VERSION 5.7 ;
  NOWIREEXTENSIONATPIN ON ;
  DIVIDERCHAR "/" ;
  BUSBITCHARS "[]" ;
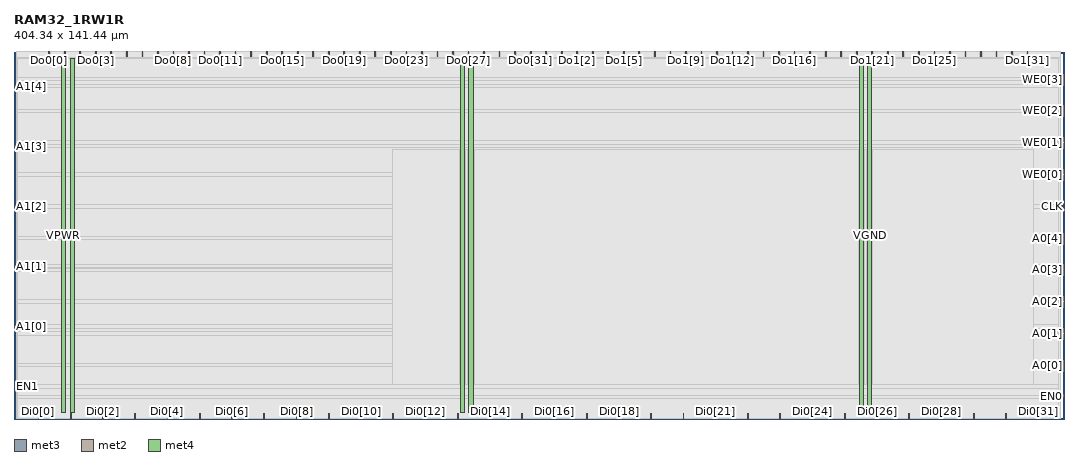
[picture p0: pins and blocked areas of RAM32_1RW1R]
MACRO RAM32_1RW1R
  CLASS BLOCK ;
  FOREIGN RAM32_1RW1R ;
  ORIGIN 0.000 0.000 ;
  SIZE 404.340 BY 141.440 ;
  PIN A0[0]
    DIRECTION INPUT ;
    USE SIGNAL ;
    ANTENNAGATEAREA 0.213000 ;
    PORT
      LAYER met3 ;
        RECT 402.340 20.440 404.340 21.040 ;
    END
  END A0[0]
  PIN A0[1]
    DIRECTION INPUT ;
    USE SIGNAL ;
    ANTENNAGATEAREA 0.213000 ;
    PORT
      LAYER met3 ;
        RECT 402.340 32.680 404.340 33.280 ;
    END
  END A0[1]
  PIN A0[2]
    DIRECTION INPUT ;
    USE SIGNAL ;
    ANTENNAGATEAREA 0.213000 ;
    PORT
      LAYER met3 ;
        RECT 402.340 44.920 404.340 45.520 ;
    END
  END A0[2]
  PIN A0[3]
    DIRECTION INPUT ;
    USE SIGNAL ;
    ANTENNAGATEAREA 0.213000 ;
    PORT
      LAYER met3 ;
        RECT 402.340 57.160 404.340 57.760 ;
    END
  END A0[3]
  PIN A0[4]
    DIRECTION INPUT ;
    USE SIGNAL ;
    ANTENNAGATEAREA 0.213000 ;
    PORT
      LAYER met3 ;
        RECT 402.340 69.400 404.340 70.000 ;
    END
  END A0[4]
  PIN A1[0]
    DIRECTION INPUT ;
    USE SIGNAL ;
    ANTENNAGATEAREA 0.213000 ;
    PORT
      LAYER met3 ;
        RECT 0.000 35.400 2.000 36.000 ;
    END
  END A1[0]
  PIN A1[1]
    DIRECTION INPUT ;
    USE SIGNAL ;
    ANTENNAGATEAREA 0.213000 ;
    PORT
      LAYER met3 ;
        RECT 0.000 58.520 2.000 59.120 ;
    END
  END A1[1]
  PIN A1[2]
    DIRECTION INPUT ;
    USE SIGNAL ;
    ANTENNAGATEAREA 0.213000 ;
    PORT
      LAYER met3 ;
        RECT 0.000 81.640 2.000 82.240 ;
    END
  END A1[2]
  PIN A1[3]
    DIRECTION INPUT ;
    USE SIGNAL ;
    ANTENNAGATEAREA 0.213000 ;
    PORT
      LAYER met3 ;
        RECT 0.000 104.760 2.000 105.360 ;
    END
  END A1[3]
  PIN A1[4]
    DIRECTION INPUT ;
    USE SIGNAL ;
    ANTENNAGATEAREA 0.213000 ;
    PORT
      LAYER met3 ;
        RECT 0.000 127.880 2.000 128.480 ;
    END
  END A1[4]
  PIN CLK
    DIRECTION INPUT ;
    USE SIGNAL ;
    ANTENNAGATEAREA 1.295400 ;
    ANTENNADIFFAREA 0.869400 ;
    PORT
      LAYER met3 ;
        RECT 402.340 81.640 404.340 82.240 ;
    END
  END CLK
  PIN Di0[0]
    DIRECTION INPUT ;
    USE SIGNAL ;
    ANTENNAGATEAREA 0.852000 ;
    PORT
      LAYER met2 ;
        RECT 9.290 0.000 9.570 2.000 ;
    END
  END Di0[0]
  PIN Di0[10]
    DIRECTION INPUT ;
    USE SIGNAL ;
    ANTENNAGATEAREA 0.852000 ;
    PORT
      LAYER met2 ;
        RECT 133.490 0.000 133.770 2.000 ;
    END
  END Di0[10]
  PIN Di0[11]
    DIRECTION INPUT ;
    USE SIGNAL ;
    ANTENNAGATEAREA 0.852000 ;
    PORT
      LAYER met2 ;
        RECT 145.910 0.000 146.190 2.000 ;
    END
  END Di0[11]
  PIN Di0[12]
    DIRECTION INPUT ;
    USE SIGNAL ;
    ANTENNAGATEAREA 0.852000 ;
    PORT
      LAYER met2 ;
        RECT 158.330 0.000 158.610 2.000 ;
    END
  END Di0[12]
  PIN Di0[13]
    DIRECTION INPUT ;
    USE SIGNAL ;
    ANTENNAGATEAREA 0.852000 ;
    PORT
      LAYER met2 ;
        RECT 170.750 0.000 171.030 2.000 ;
    END
  END Di0[13]
  PIN Di0[14]
    DIRECTION INPUT ;
    USE SIGNAL ;
    ANTENNAGATEAREA 0.852000 ;
    PORT
      LAYER met2 ;
        RECT 183.170 0.000 183.450 2.000 ;
    END
  END Di0[14]
  PIN Di0[15]
    DIRECTION INPUT ;
    USE SIGNAL ;
    ANTENNAGATEAREA 0.852000 ;
    PORT
      LAYER met2 ;
        RECT 195.590 0.000 195.870 2.000 ;
    END
  END Di0[15]
  PIN Di0[16]
    DIRECTION INPUT ;
    USE SIGNAL ;
    ANTENNAGATEAREA 0.852000 ;
    PORT
      LAYER met2 ;
        RECT 208.010 0.000 208.290 2.000 ;
    END
  END Di0[16]
  PIN Di0[17]
    DIRECTION INPUT ;
    USE SIGNAL ;
    ANTENNAGATEAREA 0.852000 ;
    PORT
      LAYER met2 ;
        RECT 220.430 0.000 220.710 2.000 ;
    END
  END Di0[17]
  PIN Di0[18]
    DIRECTION INPUT ;
    USE SIGNAL ;
    ANTENNAGATEAREA 0.852000 ;
    PORT
      LAYER met2 ;
        RECT 232.850 0.000 233.130 2.000 ;
    END
  END Di0[18]
  PIN Di0[19]
    DIRECTION INPUT ;
    USE SIGNAL ;
    ANTENNAGATEAREA 0.852000 ;
    PORT
      LAYER met2 ;
        RECT 245.270 0.000 245.550 2.000 ;
    END
  END Di0[19]
  PIN Di0[1]
    DIRECTION INPUT ;
    USE SIGNAL ;
    ANTENNAGATEAREA 0.852000 ;
    PORT
      LAYER met2 ;
        RECT 21.710 0.000 21.990 2.000 ;
    END
  END Di0[1]
  PIN Di0[20]
    DIRECTION INPUT ;
    USE SIGNAL ;
    ANTENNAGATEAREA 0.852000 ;
    PORT
      LAYER met2 ;
        RECT 257.690 0.000 257.970 2.000 ;
    END
  END Di0[20]
  PIN Di0[21]
    DIRECTION INPUT ;
    USE SIGNAL ;
    ANTENNAGATEAREA 0.852000 ;
    PORT
      LAYER met2 ;
        RECT 270.110 0.000 270.390 2.000 ;
    END
  END Di0[21]
  PIN Di0[22]
    DIRECTION INPUT ;
    USE SIGNAL ;
    ANTENNAGATEAREA 0.852000 ;
    PORT
      LAYER met2 ;
        RECT 282.530 0.000 282.810 2.000 ;
    END
  END Di0[22]
  PIN Di0[23]
    DIRECTION INPUT ;
    USE SIGNAL ;
    ANTENNAGATEAREA 0.852000 ;
    PORT
      LAYER met2 ;
        RECT 294.950 0.000 295.230 2.000 ;
    END
  END Di0[23]
  PIN Di0[24]
    DIRECTION INPUT ;
    USE SIGNAL ;
    ANTENNAGATEAREA 0.852000 ;
    PORT
      LAYER met2 ;
        RECT 307.370 0.000 307.650 2.000 ;
    END
  END Di0[24]
  PIN Di0[25]
    DIRECTION INPUT ;
    USE SIGNAL ;
    ANTENNAGATEAREA 0.852000 ;
    PORT
      LAYER met2 ;
        RECT 319.790 0.000 320.070 2.000 ;
    END
  END Di0[25]
  PIN Di0[26]
    DIRECTION INPUT ;
    USE SIGNAL ;
    ANTENNAGATEAREA 0.852000 ;
    PORT
      LAYER met2 ;
        RECT 332.210 0.000 332.490 2.000 ;
    END
  END Di0[26]
  PIN Di0[27]
    DIRECTION INPUT ;
    USE SIGNAL ;
    ANTENNAGATEAREA 0.852000 ;
    PORT
      LAYER met2 ;
        RECT 344.630 0.000 344.910 2.000 ;
    END
  END Di0[27]
  PIN Di0[28]
    DIRECTION INPUT ;
    USE SIGNAL ;
    ANTENNAGATEAREA 0.852000 ;
    PORT
      LAYER met2 ;
        RECT 357.050 0.000 357.330 2.000 ;
    END
  END Di0[28]
  PIN Di0[29]
    DIRECTION INPUT ;
    USE SIGNAL ;
    ANTENNAGATEAREA 0.852000 ;
    PORT
      LAYER met2 ;
        RECT 369.470 0.000 369.750 2.000 ;
    END
  END Di0[29]
  PIN Di0[2]
    DIRECTION INPUT ;
    USE SIGNAL ;
    ANTENNAGATEAREA 0.852000 ;
    PORT
      LAYER met2 ;
        RECT 34.130 0.000 34.410 2.000 ;
    END
  END Di0[2]
  PIN Di0[30]
    DIRECTION INPUT ;
    USE SIGNAL ;
    ANTENNAGATEAREA 0.852000 ;
    PORT
      LAYER met2 ;
        RECT 381.890 0.000 382.170 2.000 ;
    END
  END Di0[30]
  PIN Di0[31]
    DIRECTION INPUT ;
    USE SIGNAL ;
    ANTENNAGATEAREA 0.852000 ;
    PORT
      LAYER met2 ;
        RECT 394.310 0.000 394.590 2.000 ;
    END
  END Di0[31]
  PIN Di0[3]
    DIRECTION INPUT ;
    USE SIGNAL ;
    ANTENNAGATEAREA 0.852000 ;
    PORT
      LAYER met2 ;
        RECT 46.550 0.000 46.830 2.000 ;
    END
  END Di0[3]
  PIN Di0[4]
    DIRECTION INPUT ;
    USE SIGNAL ;
    ANTENNAGATEAREA 0.852000 ;
    PORT
      LAYER met2 ;
        RECT 58.970 0.000 59.250 2.000 ;
    END
  END Di0[4]
  PIN Di0[5]
    DIRECTION INPUT ;
    USE SIGNAL ;
    ANTENNAGATEAREA 0.852000 ;
    PORT
      LAYER met2 ;
        RECT 71.390 0.000 71.670 2.000 ;
    END
  END Di0[5]
  PIN Di0[6]
    DIRECTION INPUT ;
    USE SIGNAL ;
    ANTENNAGATEAREA 0.852000 ;
    PORT
      LAYER met2 ;
        RECT 83.810 0.000 84.090 2.000 ;
    END
  END Di0[6]
  PIN Di0[7]
    DIRECTION INPUT ;
    USE SIGNAL ;
    ANTENNAGATEAREA 0.852000 ;
    PORT
      LAYER met2 ;
        RECT 96.230 0.000 96.510 2.000 ;
    END
  END Di0[7]
  PIN Di0[8]
    DIRECTION INPUT ;
    USE SIGNAL ;
    ANTENNAGATEAREA 0.852000 ;
    PORT
      LAYER met2 ;
        RECT 108.650 0.000 108.930 2.000 ;
    END
  END Di0[8]
  PIN Di0[9]
    DIRECTION INPUT ;
    USE SIGNAL ;
    ANTENNAGATEAREA 0.852000 ;
    PORT
      LAYER met2 ;
        RECT 121.070 0.000 121.350 2.000 ;
    END
  END Di0[9]
  PIN Do0[0]
    DIRECTION OUTPUT ;
    USE SIGNAL ;
    ANTENNADIFFAREA 0.429000 ;
    PORT
      LAYER met2 ;
        RECT 13.430 139.440 13.710 141.440 ;
    END
  END Do0[0]
  PIN Do0[10]
    DIRECTION OUTPUT ;
    USE SIGNAL ;
    ANTENNADIFFAREA 0.429000 ;
    PORT
      LAYER met2 ;
        RECT 73.230 139.440 73.510 141.440 ;
    END
  END Do0[10]
  PIN Do0[11]
    DIRECTION OUTPUT ;
    USE SIGNAL ;
    ANTENNADIFFAREA 0.429000 ;
    PORT
      LAYER met2 ;
        RECT 79.210 139.440 79.490 141.440 ;
    END
  END Do0[11]
  PIN Do0[12]
    DIRECTION OUTPUT ;
    USE SIGNAL ;
    ANTENNADIFFAREA 0.429000 ;
    PORT
      LAYER met2 ;
        RECT 85.190 139.440 85.470 141.440 ;
    END
  END Do0[12]
  PIN Do0[13]
    DIRECTION OUTPUT ;
    USE SIGNAL ;
    ANTENNADIFFAREA 0.429000 ;
    PORT
      LAYER met2 ;
        RECT 91.170 139.440 91.450 141.440 ;
    END
  END Do0[13]
  PIN Do0[14]
    DIRECTION OUTPUT ;
    USE SIGNAL ;
    ANTENNADIFFAREA 0.429000 ;
    PORT
      LAYER met2 ;
        RECT 97.150 139.440 97.430 141.440 ;
    END
  END Do0[14]
  PIN Do0[15]
    DIRECTION OUTPUT ;
    USE SIGNAL ;
    ANTENNADIFFAREA 0.429000 ;
    PORT
      LAYER met2 ;
        RECT 103.130 139.440 103.410 141.440 ;
    END
  END Do0[15]
  PIN Do0[16]
    DIRECTION OUTPUT ;
    USE SIGNAL ;
    ANTENNADIFFAREA 0.429000 ;
    PORT
      LAYER met2 ;
        RECT 109.110 139.440 109.390 141.440 ;
    END
  END Do0[16]
  PIN Do0[17]
    DIRECTION OUTPUT ;
    USE SIGNAL ;
    ANTENNADIFFAREA 0.429000 ;
    PORT
      LAYER met2 ;
        RECT 115.090 139.440 115.370 141.440 ;
    END
  END Do0[17]
  PIN Do0[18]
    DIRECTION OUTPUT ;
    USE SIGNAL ;
    ANTENNADIFFAREA 0.429000 ;
    PORT
      LAYER met2 ;
        RECT 121.070 139.440 121.350 141.440 ;
    END
  END Do0[18]
  PIN Do0[19]
    DIRECTION OUTPUT ;
    USE SIGNAL ;
    ANTENNADIFFAREA 0.429000 ;
    PORT
      LAYER met2 ;
        RECT 127.050 139.440 127.330 141.440 ;
    END
  END Do0[19]
  PIN Do0[1]
    DIRECTION OUTPUT ;
    USE SIGNAL ;
    ANTENNADIFFAREA 0.429000 ;
    PORT
      LAYER met2 ;
        RECT 19.410 139.440 19.690 141.440 ;
    END
  END Do0[1]
  PIN Do0[20]
    DIRECTION OUTPUT ;
    USE SIGNAL ;
    ANTENNADIFFAREA 0.429000 ;
    PORT
      LAYER met2 ;
        RECT 133.030 139.440 133.310 141.440 ;
    END
  END Do0[20]
  PIN Do0[21]
    DIRECTION OUTPUT ;
    USE SIGNAL ;
    ANTENNADIFFAREA 0.429000 ;
    PORT
      LAYER met2 ;
        RECT 139.010 139.440 139.290 141.440 ;
    END
  END Do0[21]
  PIN Do0[22]
    DIRECTION OUTPUT ;
    USE SIGNAL ;
    ANTENNADIFFAREA 0.429000 ;
    PORT
      LAYER met2 ;
        RECT 144.990 139.440 145.270 141.440 ;
    END
  END Do0[22]
  PIN Do0[23]
    DIRECTION OUTPUT ;
    USE SIGNAL ;
    ANTENNADIFFAREA 0.429000 ;
    PORT
      LAYER met2 ;
        RECT 150.970 139.440 151.250 141.440 ;
    END
  END Do0[23]
  PIN Do0[24]
    DIRECTION OUTPUT ;
    USE SIGNAL ;
    ANTENNADIFFAREA 0.429000 ;
    PORT
      LAYER met2 ;
        RECT 156.950 139.440 157.230 141.440 ;
    END
  END Do0[24]
  PIN Do0[25]
    DIRECTION OUTPUT ;
    USE SIGNAL ;
    ANTENNADIFFAREA 0.429000 ;
    PORT
      LAYER met2 ;
        RECT 162.930 139.440 163.210 141.440 ;
    END
  END Do0[25]
  PIN Do0[26]
    DIRECTION OUTPUT ;
    USE SIGNAL ;
    ANTENNADIFFAREA 0.429000 ;
    PORT
      LAYER met2 ;
        RECT 168.910 139.440 169.190 141.440 ;
    END
  END Do0[26]
  PIN Do0[27]
    DIRECTION OUTPUT ;
    USE SIGNAL ;
    ANTENNADIFFAREA 0.429000 ;
    PORT
      LAYER met2 ;
        RECT 174.890 139.440 175.170 141.440 ;
    END
  END Do0[27]
  PIN Do0[28]
    DIRECTION OUTPUT ;
    USE SIGNAL ;
    ANTENNADIFFAREA 0.429000 ;
    PORT
      LAYER met2 ;
        RECT 180.870 139.440 181.150 141.440 ;
    END
  END Do0[28]
  PIN Do0[29]
    DIRECTION OUTPUT ;
    USE SIGNAL ;
    ANTENNADIFFAREA 0.429000 ;
    PORT
      LAYER met2 ;
        RECT 186.850 139.440 187.130 141.440 ;
    END
  END Do0[29]
  PIN Do0[2]
    DIRECTION OUTPUT ;
    USE SIGNAL ;
    ANTENNADIFFAREA 0.429000 ;
    PORT
      LAYER met2 ;
        RECT 25.390 139.440 25.670 141.440 ;
    END
  END Do0[2]
  PIN Do0[30]
    DIRECTION OUTPUT ;
    USE SIGNAL ;
    ANTENNADIFFAREA 0.429000 ;
    PORT
      LAYER met2 ;
        RECT 192.830 139.440 193.110 141.440 ;
    END
  END Do0[30]
  PIN Do0[31]
    DIRECTION OUTPUT ;
    USE SIGNAL ;
    ANTENNADIFFAREA 0.429000 ;
    PORT
      LAYER met2 ;
        RECT 198.810 139.440 199.090 141.440 ;
    END
  END Do0[31]
  PIN Do0[3]
    DIRECTION OUTPUT ;
    USE SIGNAL ;
    ANTENNADIFFAREA 0.429000 ;
    PORT
      LAYER met2 ;
        RECT 31.370 139.440 31.650 141.440 ;
    END
  END Do0[3]
  PIN Do0[4]
    DIRECTION OUTPUT ;
    USE SIGNAL ;
    ANTENNADIFFAREA 0.429000 ;
    PORT
      LAYER met2 ;
        RECT 37.350 139.440 37.630 141.440 ;
    END
  END Do0[4]
  PIN Do0[5]
    DIRECTION OUTPUT ;
    USE SIGNAL ;
    ANTENNADIFFAREA 0.429000 ;
    PORT
      LAYER met2 ;
        RECT 43.330 139.440 43.610 141.440 ;
    END
  END Do0[5]
  PIN Do0[6]
    DIRECTION OUTPUT ;
    USE SIGNAL ;
    ANTENNADIFFAREA 0.429000 ;
    PORT
      LAYER met2 ;
        RECT 49.310 139.440 49.590 141.440 ;
    END
  END Do0[6]
  PIN Do0[7]
    DIRECTION OUTPUT ;
    USE SIGNAL ;
    ANTENNADIFFAREA 0.429000 ;
    PORT
      LAYER met2 ;
        RECT 55.290 139.440 55.570 141.440 ;
    END
  END Do0[7]
  PIN Do0[8]
    DIRECTION OUTPUT ;
    USE SIGNAL ;
    ANTENNADIFFAREA 0.429000 ;
    PORT
      LAYER met2 ;
        RECT 61.270 139.440 61.550 141.440 ;
    END
  END Do0[8]
  PIN Do0[9]
    DIRECTION OUTPUT ;
    USE SIGNAL ;
    ANTENNADIFFAREA 0.429000 ;
    PORT
      LAYER met2 ;
        RECT 67.250 139.440 67.530 141.440 ;
    END
  END Do0[9]
  PIN Do1[0]
    DIRECTION OUTPUT ;
    USE SIGNAL ;
    ANTENNADIFFAREA 0.429000 ;
    PORT
      LAYER met2 ;
        RECT 204.790 139.440 205.070 141.440 ;
    END
  END Do1[0]
  PIN Do1[10]
    DIRECTION OUTPUT ;
    USE SIGNAL ;
    ANTENNADIFFAREA 0.429000 ;
    PORT
      LAYER met2 ;
        RECT 264.590 139.440 264.870 141.440 ;
    END
  END Do1[10]
  PIN Do1[11]
    DIRECTION OUTPUT ;
    USE SIGNAL ;
    ANTENNADIFFAREA 0.429000 ;
    PORT
      LAYER met2 ;
        RECT 270.570 139.440 270.850 141.440 ;
    END
  END Do1[11]
  PIN Do1[12]
    DIRECTION OUTPUT ;
    USE SIGNAL ;
    ANTENNADIFFAREA 0.429000 ;
    PORT
      LAYER met2 ;
        RECT 276.550 139.440 276.830 141.440 ;
    END
  END Do1[12]
  PIN Do1[13]
    DIRECTION OUTPUT ;
    USE SIGNAL ;
    ANTENNADIFFAREA 0.429000 ;
    PORT
      LAYER met2 ;
        RECT 282.530 139.440 282.810 141.440 ;
    END
  END Do1[13]
  PIN Do1[14]
    DIRECTION OUTPUT ;
    USE SIGNAL ;
    ANTENNADIFFAREA 0.429000 ;
    PORT
      LAYER met2 ;
        RECT 288.510 139.440 288.790 141.440 ;
    END
  END Do1[14]
  PIN Do1[15]
    DIRECTION OUTPUT ;
    USE SIGNAL ;
    ANTENNADIFFAREA 0.429000 ;
    PORT
      LAYER met2 ;
        RECT 294.490 139.440 294.770 141.440 ;
    END
  END Do1[15]
  PIN Do1[16]
    DIRECTION OUTPUT ;
    USE SIGNAL ;
    ANTENNADIFFAREA 0.429000 ;
    PORT
      LAYER met2 ;
        RECT 300.470 139.440 300.750 141.440 ;
    END
  END Do1[16]
  PIN Do1[17]
    DIRECTION OUTPUT ;
    USE SIGNAL ;
    ANTENNADIFFAREA 0.429000 ;
    PORT
      LAYER met2 ;
        RECT 306.450 139.440 306.730 141.440 ;
    END
  END Do1[17]
  PIN Do1[18]
    DIRECTION OUTPUT ;
    USE SIGNAL ;
    ANTENNADIFFAREA 0.429000 ;
    PORT
      LAYER met2 ;
        RECT 312.430 139.440 312.710 141.440 ;
    END
  END Do1[18]
  PIN Do1[19]
    DIRECTION OUTPUT ;
    USE SIGNAL ;
    ANTENNADIFFAREA 0.429000 ;
    PORT
      LAYER met2 ;
        RECT 318.410 139.440 318.690 141.440 ;
    END
  END Do1[19]
  PIN Do1[1]
    DIRECTION OUTPUT ;
    USE SIGNAL ;
    ANTENNADIFFAREA 0.429000 ;
    PORT
      LAYER met2 ;
        RECT 210.770 139.440 211.050 141.440 ;
    END
  END Do1[1]
  PIN Do1[20]
    DIRECTION OUTPUT ;
    USE SIGNAL ;
    ANTENNADIFFAREA 0.429000 ;
    PORT
      LAYER met2 ;
        RECT 324.390 139.440 324.670 141.440 ;
    END
  END Do1[20]
  PIN Do1[21]
    DIRECTION OUTPUT ;
    USE SIGNAL ;
    ANTENNADIFFAREA 0.429000 ;
    PORT
      LAYER met2 ;
        RECT 330.370 139.440 330.650 141.440 ;
    END
  END Do1[21]
  PIN Do1[22]
    DIRECTION OUTPUT ;
    USE SIGNAL ;
    ANTENNADIFFAREA 0.429000 ;
    PORT
      LAYER met2 ;
        RECT 336.350 139.440 336.630 141.440 ;
    END
  END Do1[22]
  PIN Do1[23]
    DIRECTION OUTPUT ;
    USE SIGNAL ;
    ANTENNADIFFAREA 0.429000 ;
    PORT
      LAYER met2 ;
        RECT 342.330 139.440 342.610 141.440 ;
    END
  END Do1[23]
  PIN Do1[24]
    DIRECTION OUTPUT ;
    USE SIGNAL ;
    ANTENNADIFFAREA 0.429000 ;
    PORT
      LAYER met2 ;
        RECT 348.310 139.440 348.590 141.440 ;
    END
  END Do1[24]
  PIN Do1[25]
    DIRECTION OUTPUT ;
    USE SIGNAL ;
    ANTENNADIFFAREA 0.429000 ;
    PORT
      LAYER met2 ;
        RECT 354.290 139.440 354.570 141.440 ;
    END
  END Do1[25]
  PIN Do1[26]
    DIRECTION OUTPUT ;
    USE SIGNAL ;
    ANTENNADIFFAREA 0.429000 ;
    PORT
      LAYER met2 ;
        RECT 360.270 139.440 360.550 141.440 ;
    END
  END Do1[26]
  PIN Do1[27]
    DIRECTION OUTPUT ;
    USE SIGNAL ;
    ANTENNADIFFAREA 0.429000 ;
    PORT
      LAYER met2 ;
        RECT 366.250 139.440 366.530 141.440 ;
    END
  END Do1[27]
  PIN Do1[28]
    DIRECTION OUTPUT ;
    USE SIGNAL ;
    ANTENNADIFFAREA 0.429000 ;
    PORT
      LAYER met2 ;
        RECT 372.230 139.440 372.510 141.440 ;
    END
  END Do1[28]
  PIN Do1[29]
    DIRECTION OUTPUT ;
    USE SIGNAL ;
    ANTENNADIFFAREA 0.429000 ;
    PORT
      LAYER met2 ;
        RECT 378.210 139.440 378.490 141.440 ;
    END
  END Do1[29]
  PIN Do1[2]
    DIRECTION OUTPUT ;
    USE SIGNAL ;
    ANTENNADIFFAREA 0.429000 ;
    PORT
      LAYER met2 ;
        RECT 216.750 139.440 217.030 141.440 ;
    END
  END Do1[2]
  PIN Do1[30]
    DIRECTION OUTPUT ;
    USE SIGNAL ;
    ANTENNADIFFAREA 0.429000 ;
    PORT
      LAYER met2 ;
        RECT 384.190 139.440 384.470 141.440 ;
    END
  END Do1[30]
  PIN Do1[31]
    DIRECTION OUTPUT ;
    USE SIGNAL ;
    ANTENNADIFFAREA 0.429000 ;
    PORT
      LAYER met2 ;
        RECT 390.170 139.440 390.450 141.440 ;
    END
  END Do1[31]
  PIN Do1[3]
    DIRECTION OUTPUT ;
    USE SIGNAL ;
    ANTENNADIFFAREA 0.429000 ;
    PORT
      LAYER met2 ;
        RECT 222.730 139.440 223.010 141.440 ;
    END
  END Do1[3]
  PIN Do1[4]
    DIRECTION OUTPUT ;
    USE SIGNAL ;
    ANTENNADIFFAREA 0.429000 ;
    PORT
      LAYER met2 ;
        RECT 228.710 139.440 228.990 141.440 ;
    END
  END Do1[4]
  PIN Do1[5]
    DIRECTION OUTPUT ;
    USE SIGNAL ;
    ANTENNADIFFAREA 0.429000 ;
    PORT
      LAYER met2 ;
        RECT 234.690 139.440 234.970 141.440 ;
    END
  END Do1[5]
  PIN Do1[6]
    DIRECTION OUTPUT ;
    USE SIGNAL ;
    ANTENNADIFFAREA 0.429000 ;
    PORT
      LAYER met2 ;
        RECT 240.670 139.440 240.950 141.440 ;
    END
  END Do1[6]
  PIN Do1[7]
    DIRECTION OUTPUT ;
    USE SIGNAL ;
    ANTENNADIFFAREA 0.429000 ;
    PORT
      LAYER met2 ;
        RECT 246.650 139.440 246.930 141.440 ;
    END
  END Do1[7]
  PIN Do1[8]
    DIRECTION OUTPUT ;
    USE SIGNAL ;
    ANTENNADIFFAREA 0.429000 ;
    PORT
      LAYER met2 ;
        RECT 252.630 139.440 252.910 141.440 ;
    END
  END Do1[8]
  PIN Do1[9]
    DIRECTION OUTPUT ;
    USE SIGNAL ;
    ANTENNADIFFAREA 0.429000 ;
    PORT
      LAYER met2 ;
        RECT 258.610 139.440 258.890 141.440 ;
    END
  END Do1[9]
  PIN EN0
    DIRECTION INPUT ;
    USE SIGNAL ;
    ANTENNAGATEAREA 0.213000 ;
    PORT
      LAYER met3 ;
        RECT 402.340 8.200 404.340 8.800 ;
    END
  END EN0
  PIN EN1
    DIRECTION INPUT ;
    USE SIGNAL ;
    ANTENNAGATEAREA 0.213000 ;
    PORT
      LAYER met3 ;
        RECT 0.000 12.280 2.000 12.880 ;
    END
  END EN1
  PIN VGND
    DIRECTION INOUT ;
    USE GROUND ;
    PORT
      LAYER met4 ;
        RECT 21.580 2.480 23.180 138.960 ;
    END
    PORT
      LAYER met4 ;
        RECT 175.180 2.480 176.780 138.960 ;
    END
    PORT
      LAYER met4 ;
        RECT 328.780 2.480 330.380 138.960 ;
    END
  END VGND
  PIN VPWR
    DIRECTION INOUT ;
    USE POWER ;
    PORT
      LAYER met4 ;
        RECT 18.280 2.480 19.880 138.960 ;
    END
    PORT
      LAYER met4 ;
        RECT 171.880 2.480 173.480 138.960 ;
    END
    PORT
      LAYER met4 ;
        RECT 325.480 2.480 327.080 138.960 ;
    END
  END VPWR
  PIN WE0[0]
    DIRECTION INPUT ;
    USE SIGNAL ;
    ANTENNAGATEAREA 0.213000 ;
    PORT
      LAYER met3 ;
        RECT 402.340 93.880 404.340 94.480 ;
    END
  END WE0[0]
  PIN WE0[1]
    DIRECTION INPUT ;
    USE SIGNAL ;
    ANTENNAGATEAREA 0.213000 ;
    PORT
      LAYER met3 ;
        RECT 402.340 106.120 404.340 106.720 ;
    END
  END WE0[1]
  PIN WE0[2]
    DIRECTION INPUT ;
    USE SIGNAL ;
    ANTENNAGATEAREA 0.213000 ;
    PORT
      LAYER met3 ;
        RECT 402.340 118.360 404.340 118.960 ;
    END
  END WE0[2]
  PIN WE0[3]
    DIRECTION INPUT ;
    USE SIGNAL ;
    ANTENNAGATEAREA 0.213000 ;
    PORT
      LAYER met3 ;
        RECT 402.340 130.600 404.340 131.200 ;
    END
  END WE0[3]
  OBS
      LAYER nwell ;
        RECT 2.570 2.635 401.770 138.805 ;
      LAYER li1 ;
        RECT 2.760 2.635 401.580 138.805 ;
      LAYER met1 ;
        RECT 0.990 0.040 402.890 141.400 ;
      LAYER met2 ;
        RECT 1.020 139.160 13.150 141.430 ;
        RECT 13.990 139.160 19.130 141.430 ;
        RECT 19.970 139.160 25.110 141.430 ;
        RECT 25.950 139.160 31.090 141.430 ;
        RECT 31.930 139.160 37.070 141.430 ;
        RECT 37.910 139.160 43.050 141.430 ;
        RECT 43.890 139.160 49.030 141.430 ;
        RECT 49.870 139.160 55.010 141.430 ;
        RECT 55.850 139.160 60.990 141.430 ;
        RECT 61.830 139.160 66.970 141.430 ;
        RECT 67.810 139.160 72.950 141.430 ;
        RECT 73.790 139.160 78.930 141.430 ;
        RECT 79.770 139.160 84.910 141.430 ;
        RECT 85.750 139.160 90.890 141.430 ;
        RECT 91.730 139.160 96.870 141.430 ;
        RECT 97.710 139.160 102.850 141.430 ;
        RECT 103.690 139.160 108.830 141.430 ;
        RECT 109.670 139.160 114.810 141.430 ;
        RECT 115.650 139.160 120.790 141.430 ;
        RECT 121.630 139.160 126.770 141.430 ;
        RECT 127.610 139.160 132.750 141.430 ;
        RECT 133.590 139.160 138.730 141.430 ;
        RECT 139.570 139.160 144.710 141.430 ;
        RECT 145.550 139.160 150.690 141.430 ;
        RECT 151.530 139.160 156.670 141.430 ;
        RECT 157.510 139.160 162.650 141.430 ;
        RECT 163.490 139.160 168.630 141.430 ;
        RECT 169.470 139.160 174.610 141.430 ;
        RECT 175.450 139.160 180.590 141.430 ;
        RECT 181.430 139.160 186.570 141.430 ;
        RECT 187.410 139.160 192.550 141.430 ;
        RECT 193.390 139.160 198.530 141.430 ;
        RECT 199.370 139.160 204.510 141.430 ;
        RECT 205.350 139.160 210.490 141.430 ;
        RECT 211.330 139.160 216.470 141.430 ;
        RECT 217.310 139.160 222.450 141.430 ;
        RECT 223.290 139.160 228.430 141.430 ;
        RECT 229.270 139.160 234.410 141.430 ;
        RECT 235.250 139.160 240.390 141.430 ;
        RECT 241.230 139.160 246.370 141.430 ;
        RECT 247.210 139.160 252.350 141.430 ;
        RECT 253.190 139.160 258.330 141.430 ;
        RECT 259.170 139.160 264.310 141.430 ;
        RECT 265.150 139.160 270.290 141.430 ;
        RECT 271.130 139.160 276.270 141.430 ;
        RECT 277.110 139.160 282.250 141.430 ;
        RECT 283.090 139.160 288.230 141.430 ;
        RECT 289.070 139.160 294.210 141.430 ;
        RECT 295.050 139.160 300.190 141.430 ;
        RECT 301.030 139.160 306.170 141.430 ;
        RECT 307.010 139.160 312.150 141.430 ;
        RECT 312.990 139.160 318.130 141.430 ;
        RECT 318.970 139.160 324.110 141.430 ;
        RECT 324.950 139.160 330.090 141.430 ;
        RECT 330.930 139.160 336.070 141.430 ;
        RECT 336.910 139.160 342.050 141.430 ;
        RECT 342.890 139.160 348.030 141.430 ;
        RECT 348.870 139.160 354.010 141.430 ;
        RECT 354.850 139.160 359.990 141.430 ;
        RECT 360.830 139.160 365.970 141.430 ;
        RECT 366.810 139.160 371.950 141.430 ;
        RECT 372.790 139.160 377.930 141.430 ;
        RECT 378.770 139.160 383.910 141.430 ;
        RECT 384.750 139.160 389.890 141.430 ;
        RECT 390.730 139.160 402.860 141.430 ;
        RECT 1.020 2.280 402.860 139.160 ;
        RECT 1.020 0.010 9.010 2.280 ;
        RECT 9.850 0.010 21.430 2.280 ;
        RECT 22.270 0.010 33.850 2.280 ;
        RECT 34.690 0.010 46.270 2.280 ;
        RECT 47.110 0.010 58.690 2.280 ;
        RECT 59.530 0.010 71.110 2.280 ;
        RECT 71.950 0.010 83.530 2.280 ;
        RECT 84.370 0.010 95.950 2.280 ;
        RECT 96.790 0.010 108.370 2.280 ;
        RECT 109.210 0.010 120.790 2.280 ;
        RECT 121.630 0.010 133.210 2.280 ;
        RECT 134.050 0.010 145.630 2.280 ;
        RECT 146.470 0.010 158.050 2.280 ;
        RECT 158.890 0.010 170.470 2.280 ;
        RECT 171.310 0.010 182.890 2.280 ;
        RECT 183.730 0.010 195.310 2.280 ;
        RECT 196.150 0.010 207.730 2.280 ;
        RECT 208.570 0.010 220.150 2.280 ;
        RECT 220.990 0.010 232.570 2.280 ;
        RECT 233.410 0.010 244.990 2.280 ;
        RECT 245.830 0.010 257.410 2.280 ;
        RECT 258.250 0.010 269.830 2.280 ;
        RECT 270.670 0.010 282.250 2.280 ;
        RECT 283.090 0.010 294.670 2.280 ;
        RECT 295.510 0.010 307.090 2.280 ;
        RECT 307.930 0.010 319.510 2.280 ;
        RECT 320.350 0.010 331.930 2.280 ;
        RECT 332.770 0.010 344.350 2.280 ;
        RECT 345.190 0.010 356.770 2.280 ;
        RECT 357.610 0.010 369.190 2.280 ;
        RECT 370.030 0.010 381.610 2.280 ;
        RECT 382.450 0.010 394.030 2.280 ;
        RECT 394.870 0.010 402.860 2.280 ;
      LAYER met3 ;
        RECT 1.230 131.600 402.340 138.885 ;
        RECT 1.230 130.200 401.940 131.600 ;
        RECT 1.230 128.880 402.340 130.200 ;
        RECT 2.400 127.480 402.340 128.880 ;
        RECT 1.230 119.360 402.340 127.480 ;
        RECT 1.230 117.960 401.940 119.360 ;
        RECT 1.230 107.120 402.340 117.960 ;
        RECT 1.230 105.760 401.940 107.120 ;
        RECT 2.400 105.720 401.940 105.760 ;
        RECT 2.400 104.360 402.340 105.720 ;
        RECT 1.230 94.880 402.340 104.360 ;
        RECT 1.230 93.480 401.940 94.880 ;
        RECT 1.230 82.640 402.340 93.480 ;
        RECT 2.400 81.240 401.940 82.640 ;
        RECT 1.230 70.400 402.340 81.240 ;
        RECT 1.230 69.000 401.940 70.400 ;
        RECT 1.230 59.520 402.340 69.000 ;
        RECT 2.400 58.160 402.340 59.520 ;
        RECT 2.400 58.120 401.940 58.160 ;
        RECT 1.230 56.760 401.940 58.120 ;
        RECT 1.230 45.920 402.340 56.760 ;
        RECT 1.230 44.520 401.940 45.920 ;
        RECT 1.230 36.400 402.340 44.520 ;
        RECT 2.400 35.000 402.340 36.400 ;
        RECT 1.230 33.680 402.340 35.000 ;
        RECT 1.230 32.280 401.940 33.680 ;
        RECT 1.230 21.440 402.340 32.280 ;
        RECT 1.230 20.040 401.940 21.440 ;
        RECT 1.230 13.280 402.340 20.040 ;
        RECT 2.400 11.880 402.340 13.280 ;
        RECT 1.230 9.200 402.340 11.880 ;
        RECT 1.230 7.800 401.940 9.200 ;
        RECT 1.230 0.175 402.340 7.800 ;
      LAYER met4 ;
        RECT 145.655 13.095 171.480 103.865 ;
        RECT 173.880 13.095 174.780 103.865 ;
        RECT 177.180 13.095 325.080 103.865 ;
        RECT 327.480 13.095 328.380 103.865 ;
        RECT 330.780 13.095 392.545 103.865 ;
  END
END RAM32_1RW1R
END LIBRARY

